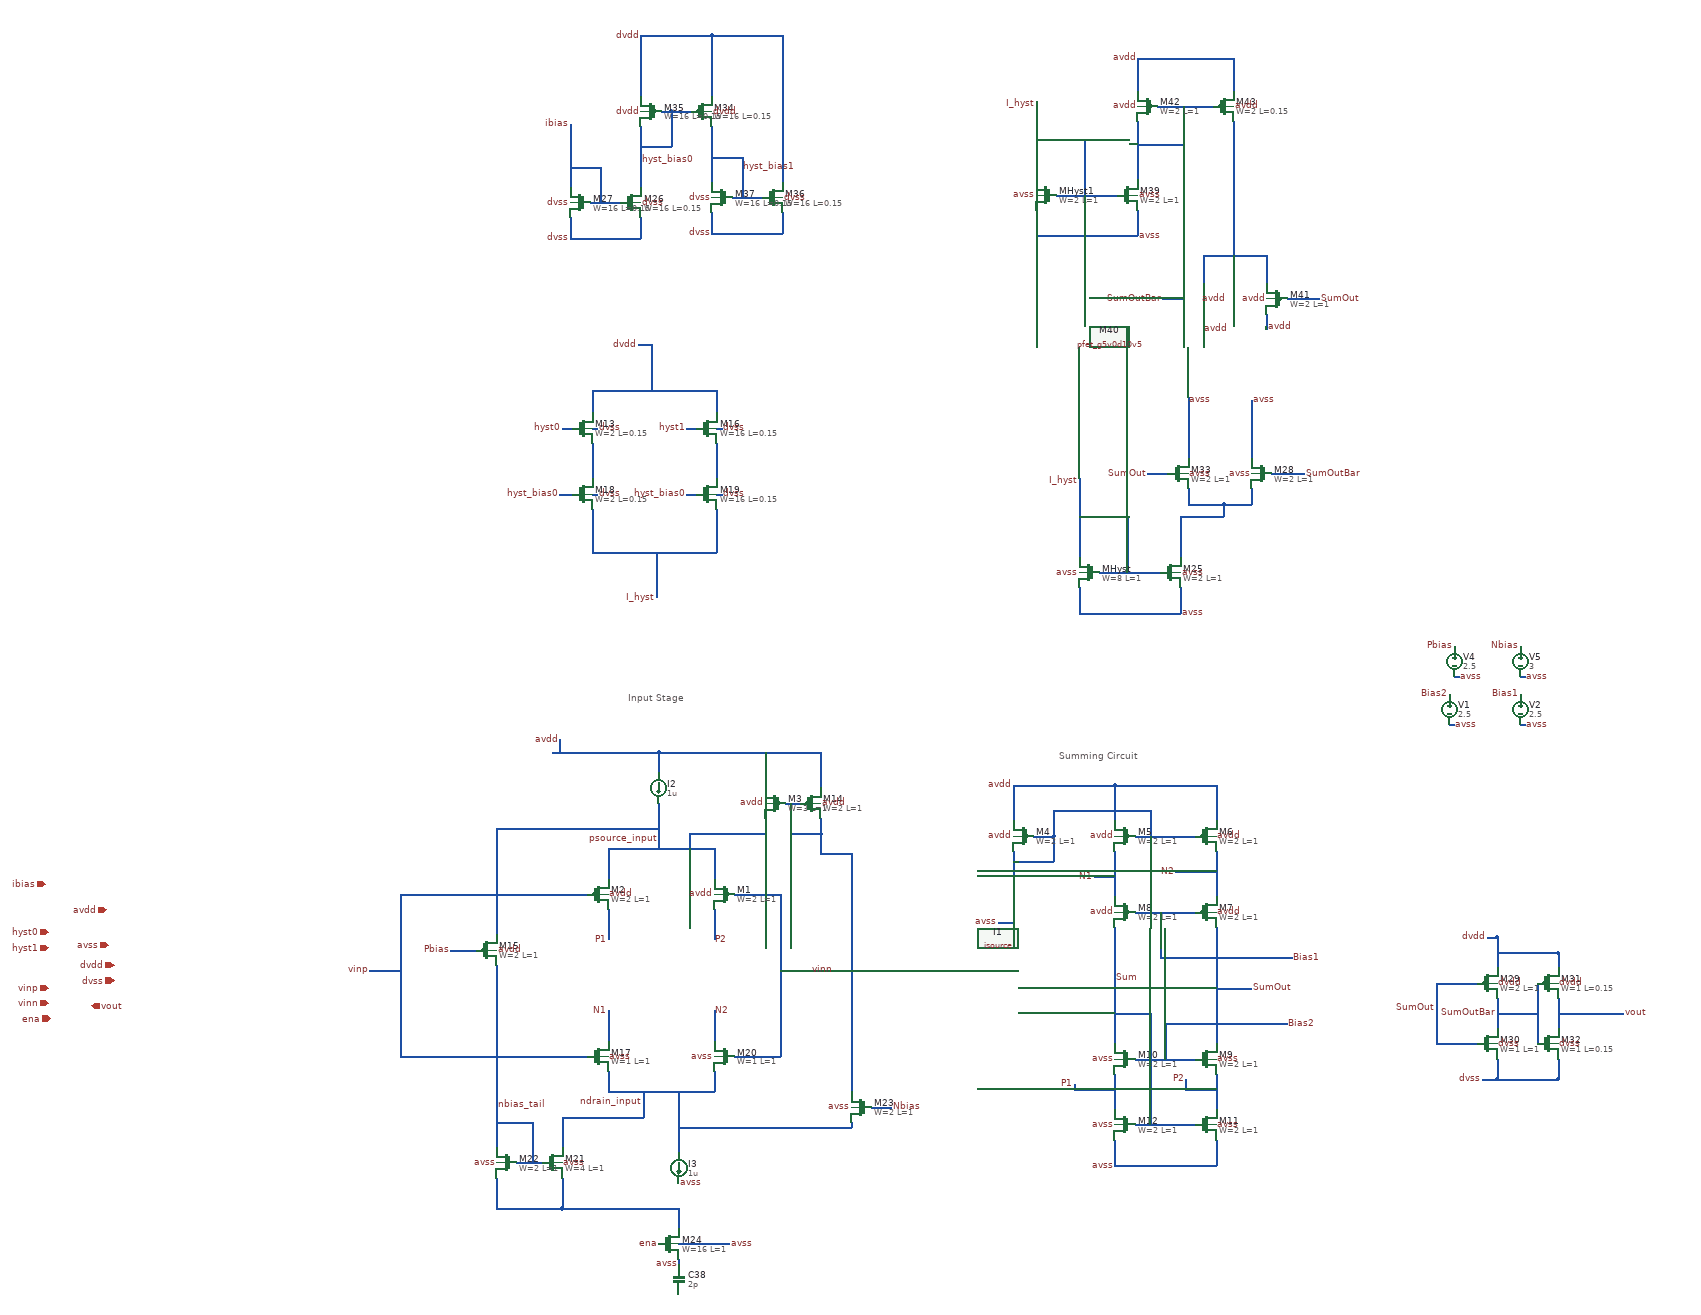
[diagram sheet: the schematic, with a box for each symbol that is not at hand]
v {xschem version=3.4.4 file_version=1.2
}
G {}
K {}
V {}
S {}
E {}
T {Summing Circuit} 2105 -1180 0 0 0.5 0.5 {}
T {Input Stage} 1255 -1295 0 0 0.5 0.5 {}
N 1185 -1815 1195 -1815 {
lab=dvss}
N 1310 -1500 1310 -1480 {
lab=I_hyst}
N 1430 -1815 1440 -1815 {
lab=dvss}
N 1370 -1815 1390 -1815 {
lab=hyst1}
N 1430 -1785 1430 -1715 {
lab=#net1}
N 1430 -1685 1440 -1685 {
lab=dvss}
N 1185 -1785 1185 -1715 {
lab=#net2}
N 1185 -1785 1185 -1715 {
lab=#net2}
N 1430 -1655 1430 -1625 {
lab=I_hyst}
N 1185 -1635 1185 -1570 {
lab=I_hyst}
N 1185 -1655 1185 -1635 {
lab=I_hyst}
N 1430 -1625 1430 -1570 {
lab=I_hyst}
N 1185 -1685 1195 -1685 {
lab=dvss}
N 1430 -1890 1430 -1845 {
lab=dvdd}
N 1185 -1890 1185 -1845 {
lab=dvdd}
N 1185 -1570 1430 -1570 {
lab=I_hyst}
N 1370 -1685 1390 -1685 {
lab=hyst_bias0}
N 1120 -1685 1145 -1685 {
lab=hyst_bias0}
N 1125 -1815 1145 -1815 {
lab=hyst0}
N 2970 -690 2970 -630 {
lab=SumOutBar}
N 3090 -660 3220 -660 {
lab=vout}
N 2970 -810 2970 -750 {
lab=dvdd}
N 2950 -810 2970 -810 {
lab=dvdd}
N 2970 -570 2970 -530 {
lab=dvss}
N 2940 -530 2970 -530 {
lab=dvss}
N 2885 -1325 2895 -1325 {
lab=avss}
N 3015 -1325 3025 -1325 {
lab=avss}
N 3090 -690 3090 -630 {
lab=vout}
N 3050 -720 3050 -600 {
lab=SumOutBar}
N 3090 -780 3090 -750 {
lab=dvdd}
N 2970 -780 3090 -780 {
lab=dvdd}
N 3090 -570 3090 -530 {
lab=dvss}
N 2970 -530 3090 -530 {
lab=dvss}
N 2970 -690 2970 -630 {
lab=SumOutBar}
N 2880 -720 2930 -720 {
lab=SumOut}
N 2880 -600 2930 -600 {
lab=SumOut}
N 3090 -660 3220 -660 {
lab=vout}
N 2970 -810 2970 -750 {
lab=dvdd}
N 2950 -810 2970 -810 {
lab=dvdd}
N 2970 -570 2970 -530 {
lab=dvss}
N 2940 -530 2970 -530 {
lab=dvss}
N 3090 -690 3090 -630 {
lab=vout}
N 3050 -720 3050 -600 {
lab=SumOutBar}
N 3090 -780 3090 -750 {
lab=dvdd}
N 2970 -780 3090 -780 {
lab=dvdd}
N 3090 -570 3090 -530 {
lab=dvss}
N 2970 -530 3090 -530 {
lab=dvss}
N 2970 -660 3050 -660 {
lab=SumOutBar}
N 2015 -980 2015 -930 {
lab=#net3}
N 2015 -960 2095 -960 {
lab=#net3}
N 2095 -1010 2095 -960 {
lab=#net3}
N 2055 -1010 2095 -1010 {
lab=#net3}
N 2015 -1110 2015 -1040 {
lab=avdd}
N 2015 -1110 2215 -1110 {
lab=avdd}
N 2215 -1110 2215 -1040 {
lab=avdd}
N 2215 -1110 2395 -1110 {
lab=avdd}
N 2415 -1110 2415 -1040 {
lab=avdd}
N 2395 -1110 2415 -1110 {
lab=avdd}
N 2255 -1010 2375 -1010 {
lab=#net3}
N 2285 -1060 2285 -1010 {
lab=#net3}
N 2095 -1060 2285 -1060 {
lab=#net3}
N 2095 -1060 2095 -1010 {
lab=#net3}
N 2215 -980 2215 -920 {
lab=N1}
N 2415 -980 2415 -890 {
lab=N2}
N 2335 -940 2415 -940 {
lab=N2}
N 2335 -860 2375 -860 {
lab=Bias1}
N 2255 -860 2335 -860 {
lab=Bias1}
N 2215 -920 2215 -890 {
lab=N1}
N 2415 -830 2415 -600 {
lab=SumOut}
N 2215 -830 2215 -600 {
lab=Sum}
N 2255 -570 2375 -570 {
lab=Bias2}
N 2415 -540 2415 -470 {
lab=P2}
N 2355 -510 2415 -510 {
lab=P2}
N 2355 -530 2355 -510 {
lab=P2}
N 2215 -540 2215 -470 {
lab=P1}
N 2255 -440 2375 -440 {
lab=Sum}
N 2215 -410 2215 -360 {
lab=avss}
N 2215 -360 2415 -360 {
lab=avss}
N 2415 -410 2415 -360 {
lab=avss}
N 2135 -510 2215 -510 {
lab=P1}
N 2135 -520 2135 -510 {
lab=P1}
N 2285 -660 2285 -440 {
lab=Sum}
N 2215 -660 2285 -660 {
lab=Sum}
N 2175 -930 2215 -930 {
lab=N1}
N 2305 -860 2305 -770 {
lab=Bias1}
N 2305 -770 2565 -770 {
lab=Bias1}
N 2315 -640 2315 -570 {
lab=Bias2}
N 2315 -640 2555 -640 {
lab=Bias2}
N 2015 -870 2015 -840 {
lab=avss}
N 1985 -840 2015 -840 {
lab=avss}
N 2415 -710 2485 -710 {
lab=SumOut}
N 1355 -205 1455 -205 {lab=avss}
N 1355 -175 1355 -145 {lab=avss}
N 1425 -985 1425 -925 {
lab=psource_input}
N 1215 -985 1425 -985 {
lab=psource_input}
N 1215 -985 1215 -925 {
lab=psource_input}
N 1315 -1015 1315 -985 {
lab=psource_input}
N 1265 -1175 1315 -1175 {
lab=avdd}
N 1565 -1075 1595 -1075 {
lab=#net4}
N 1315 -1175 1585 -1175 {
lab=avdd}
N 1635 -1175 1635 -1105 {
lab=avdd}
N 1525 -1175 1525 -1105 {
lab=avdd}
N 1575 -1075 1575 -1015 {
lab=#net4}
N 1575 -1015 1635 -1015 {
lab=#net4}
N 1635 -1045 1635 -1015 {
lab=#net4}
N 1525 -1045 1525 -1015 {
lab=psource_input}
N 1375 -1015 1475 -1015 {
lab=psource_input}
N 1375 -1015 1375 -985 {
lab=psource_input}
N 1425 -865 1425 -805 {
lab=P2}
N 1215 -865 1215 -805 {
lab=P1}
N 1105 -1025 1315 -1025 {
lab=psource_input}
N 995 -975 995 -925 {
lab=psource_input}
N 995 -1025 995 -975 {
lab=psource_input}
N 1045 -1025 1105 -1025 {
lab=psource_input}
N 905 -785 955 -785 {
lab=Pbias}
N 995 -925 995 -815 {
lab=psource_input}
N 805 -895 1175 -895 {
lab=vinp}
N 1425 -655 1425 -605 {
lab=N2}
N 1215 -665 1215 -605 {
lab=N1}
N 1425 -665 1425 -655 {
lab=N2}
N 1035 -365 1085 -365 {
lab=nbias_tail}
N 1215 -545 1215 -505 {
lab=ndrain_input}
N 1215 -505 1425 -505 {
lab=ndrain_input}
N 1425 -545 1425 -505 {
lab=ndrain_input}
N 1285 -505 1285 -455 {
lab=ndrain_input}
N 1125 -455 1285 -455 {
lab=ndrain_input}
N 1125 -455 1125 -395 {
lab=ndrain_input}
N 995 -1025 1045 -1025 {
lab=psource_input}
N 995 -755 995 -395 {
lab=nbias_tail}
N 805 -575 1175 -575 {
lab=vinp}
N 995 -335 995 -275 {
lab=#net5}
N 995 -275 1125 -275 {
lab=#net5}
N 1125 -335 1125 -275 {
lab=#net5}
N 1465 -575 1555 -575 {
lab=vinn}
N 1355 -505 1355 -385 {
lab=ndrain_input}
N 1475 -1015 1525 -1015 {
lab=psource_input}
N 1585 -1175 1635 -1175 {
lab=avdd}
N 1465 -895 1485 -895 {
lab=vinn}
N 1485 -895 1505 -895 {
lab=vinn}
N 1555 -895 1555 -575 {
lab=vinn}
N 1505 -895 1555 -895 {
lab=vinn}
N 1555 -745 1585 -745 {
lab=vinn}
N 1585 -745 1615 -745 {
lab=vinn}
N 1065 -445 1065 -365 {
lab=nbias_tail}
N 995 -445 1065 -445 {
lab=nbias_tail}
N 1355 -435 1635 -435 {
lab=ndrain_input}
N 1635 -435 1695 -435 {
lab=ndrain_input}
N 1695 -445 1695 -435 {
lab=ndrain_input}
N 1695 -975 1695 -505 {
lab=#net4}
N 1635 -975 1695 -975 {
lab=#net4}
N 1635 -1015 1635 -975 {
lab=#net4}
N 1735 -475 1775 -475 {
lab=Nbias}
N 1105 -1175 1265 -1175 {
lab=avdd}
N 1120 -1200 1120 -1175 {
lab=avdd}
N 1315 -1025 1315 -1015 {
lab=psource_input}
N 1125 -275 1195 -275 {
lab=#net5}
N 805 -895 805 -575 {
lab=vinp}
N 745 -745 775 -745 {
lab=vinp}
N 775 -745 805 -745 {
lab=vinp}
N 1315 -1075 1315 -1020 {
lab=psource_input}
N 1315 -1175 1315 -1135 {
lab=avdd}
N 2185 -1530 2305 -1530 {
lab=I_hyst}
N 2145 -1500 2145 -1450 {
lab=avss}
N 2145 -1450 2345 -1450 {
lab=avss}
N 2345 -1500 2345 -1450 {
lab=avss}
N 2145 -1715 2145 -1560 {
lab=I_hyst}
N 2240 -1640 2240 -1530 {
lab=I_hyst}
N 2145 -1640 2240 -1640 {
lab=I_hyst}
N 2280 -1725 2320 -1725 {
lab=SumOut}
N 2345 -1640 2360 -1640 {
lab=#net6}
N 2345 -1640 2345 -1560 {
lab=#net6}
N 2360 -1640 2430 -1640 {
lab=#net6}
N 2430 -1665 2430 -1640 {
lab=#net6}
N 2360 -1665 2430 -1665 {
lab=#net6}
N 2360 -1695 2360 -1665 {
lab=#net6}
N 2430 -1665 2485 -1665 {
lab=#net6}
N 2485 -1695 2485 -1665 {
lab=#net6}
N 2485 -1870 2485 -1755 {
lab=avss}
N 2360 -1805 2360 -1755 {
lab=avss}
N 2525 -1725 2590 -1725 {
lab=SumOutBar}
N 1140 -2230 1140 -2190 {
lab=dvss}
N 1140 -2190 1280 -2190 {
lab=dvss}
N 1280 -2230 1280 -2190 {
lab=dvss}
N 1180 -2260 1240 -2260 {
lab=ibias}
N 1140 -2415 1140 -2290 {
lab=ibias}
N 1200 -2330 1200 -2260 {
lab=ibias}
N 1140 -2330 1200 -2330 {
lab=ibias}
N 1280 -2410 1280 -2290 {
lab=hyst_bias0}
N 1280 -2370 1340 -2370 {
lab=hyst_bias0}
N 1340 -2440 1340 -2370 {
lab=hyst_bias0}
N 1320 -2440 1340 -2440 {
lab=hyst_bias0}
N 1340 -2440 1380 -2440 {
lab=hyst_bias0}
N 1280 -2590 1280 -2470 {
lab=dvdd}
N 1280 -2590 1420 -2590 {
lab=dvdd}
N 1420 -2590 1420 -2470 {
lab=dvdd}
N 1185 -1890 1430 -1890 {
lab=dvdd}
N 1300 -1980 1300 -1890 {
lab=dvdd}
N 1275 -1980 1300 -1980 {
lab=dvdd}
N 1420 -2240 1420 -2200 {
lab=dvss}
N 1420 -2200 1560 -2200 {
lab=dvss}
N 1560 -2240 1560 -2200 {
lab=dvss}
N 1460 -2270 1520 -2270 {
lab=hyst_bias1}
N 1420 -2410 1420 -2300 {
lab=hyst_bias1}
N 1480 -2350 1480 -2270 {
lab=hyst_bias1}
N 1420 -2350 1480 -2350 {
lab=hyst_bias1}
N 1560 -2590 1560 -2300 {
lab=dvdd}
N 1420 -2590 1560 -2590 {
lab=dvdd}
N 3015 -1230 3025 -1230 {
lab=avss}
N 2850 -720 2850 -600 {
lab=SumOut}
N 2850 -600 2880 -600 {
lab=SumOut}
N 2850 -720 2880 -720 {
lab=SumOut}
N 1195 -275 1355 -275 {
lab=#net5}
N 1355 -275 1355 -240 {
lab=#net5}
N 1355 -240 1355 -235 {
lab=#net5}
N 1310 -1570 1310 -1560 {
lab=I_hyst}
N 1310 -1560 1310 -1500 {
lab=I_hyst}
N 2360 -1875 2360 -1805 {
lab=avss}
N 2875 -1230 2885 -1230 {
lab=avss}
N 2100 -2275 2220 -2275 {
lab=I_hyst}
N 2060 -2245 2060 -2195 {
lab=avss}
N 2060 -2195 2260 -2195 {
lab=avss}
N 2260 -2245 2260 -2195 {
lab=avss}
N 2060 -2460 2060 -2305 {
lab=I_hyst}
N 2155 -2385 2155 -2275 {
lab=I_hyst}
N 2060 -2385 2155 -2385 {
lab=I_hyst}
N 2310 -2070 2350 -2070 {
lab=SumOutBar}
N 2260 -2385 2260 -2305 {
lab=#net7}
N 2390 -2040 2390 -2010 {
lab=avdd}
N 2515 -2040 2515 -2010 {
lab=avdd}
N 2390 -2150 2390 -2100 {
lab=#net8}
N 2555 -2070 2620 -2070 {
lab=SumOut}
N 2515 -2155 2515 -2100 {
lab=#net8}
N 2390 -2155 2515 -2155 {
lab=#net8}
N 2390 -2155 2390 -2150 {
lab=#net8}
N 2260 -2420 2260 -2385 {
lab=#net7}
N 2300 -2450 2410 -2450 {
lab=#net7}
N 2450 -2420 2450 -2155 {
lab=#net8}
N 2260 -2545 2260 -2480 {
lab=avdd}
N 2260 -2545 2450 -2545 {
lab=avdd}
N 2450 -2545 2450 -2480 {
lab=avdd}
N 2260 -2375 2350 -2375 {
lab=#net7}
N 2350 -2450 2350 -2375 {
lab=#net7}
C {devices/ipin.sym} 110 -710 0 0 {name=p48 lab=vinp
}
C {devices/ipin.sym} 110 -680 0 0 {name=p4 lab=vinn
}
C {devices/ipin.sym} 110 -820 0 0 {name=p19 lab=hyst0
}
C {devices/ipin.sym} 110 -790 0 0 {name=p20 lab=hyst1
}
C {devices/lab_pin.sym} 1310 -1480 0 0 {name=p31 sig_type=std_logic lab=I_hyst

}
C {devices/ipin.sym} 225 -865 0 0 {name=p37 lab=avdd
}
C {devices/ipin.sym} 230 -795 0 0 {name=p38 lab=avss
}
C {devices/ipin.sym} 240 -755 0 0 {name=p39 lab=dvdd
}
C {devices/ipin.sym} 240 -725 0 0 {name=p40 lab=dvss
}
C {devices/opin.sym} 195 -675 0 0 { name=p116 lab=vout}
C {devices/ipin.sym} 115 -650 0 0 {name=p42 lab=ena
}
C {devices/lab_pin.sym} 1370 -1815 0 0 {name=p18 sig_type=std_logic lab=hyst1

}
C {sky130_fd_pr/nfet_01v8.sym} 1410 -1815 0 0 {name=M16
L=0.15
W=16
mult=8 nf=1
model=nfet_01v8
spiceprefix=X}
C {sky130_fd_pr/nfet_01v8.sym} 1410 -1685 0 0 {name=M19
L=0.15
W=16
mult=8 nf=1
model=nfet_01v8
spiceprefix=X}
C {devices/ipin.sym} 105 -915 0 0 {name=p27 lab=ibias
}
C {devices/lab_pin.sym} 1195 -1685 0 1 {name=p33 sig_type=std_logic lab=dvss

}
C {devices/lab_pin.sym} 1125 -1815 0 0 {name=p25 sig_type=std_logic lab=hyst0

}
C {devices/lab_pin.sym} 1120 -1685 0 0 {name=p26 sig_type=std_logic lab=hyst_bias0


}
C {devices/lab_pin.sym} 1195 -1815 0 1 {name=p23 sig_type=std_logic lab=dvss

}
C {devices/lab_pin.sym} 1440 -1685 0 1 {name=p30 sig_type=std_logic lab=dvss

}
C {devices/vsource.sym} 2885 -1355 0 0 {name=V4 value=2.5 savecurrent=false}
C {devices/vsource.sym} 3015 -1355 0 0 {name=V5 value=3 savecurrent=false}
C {devices/lab_pin.sym} 3015 -1385 0 0 {name=p36 sig_type=std_logic lab=Nbias


}
C {devices/lab_pin.sym} 2895 -1325 0 1 {name=p32 lab=avss
}
C {devices/lab_pin.sym} 3025 -1325 0 1 {name=p35 lab=avss
}
C {sky130_fd_pr/pfet_01v8.sym} 2950 -720 0 0 {name=M29
L=1
W=2
nf=1
mult=2
ad="'int((nf+1)/2) * W/nf * 0.29'" 
pd="'2*int((nf+1)/2) * (W/nf + 0.29)'"
as="'int((nf+2)/2) * W/nf * 0.29'" 
ps="'2*int((nf+2)/2) * (W/nf + 0.29)'"
nrd="'0.29 / W'" nrs="'0.29 / W'"
sa=0 sb=0 sd=0
model=pfet_01v8
spiceprefix=X
}
C {devices/lab_pin.sym} 3220 -660 0 1 {name=l39 lab=vout
}
C {devices/lab_pin.sym} 2950 -810 0 0 {name=l40 lab=dvdd
}
C {devices/lab_pin.sym} 2940 -530 0 0 {name=l41 lab=dvss
}
C {sky130_fd_pr/nfet_01v8.sym} 2950 -600 0 0 {name=M30
L=1
W=1
nf=1 
mult=2
ad="'int((nf+1)/2) * W/nf * 0.29'" 
pd="'2*int((nf+1)/2) * (W/nf + 0.29)'"
as="'int((nf+2)/2) * W/nf * 0.29'" 
ps="'2*int((nf+2)/2) * (W/nf + 0.29)'"
nrd="'0.29 / W'" nrs="'0.29 / W'"
sa=0 sb=0 sd=0
model=nfet_01v8
spiceprefix=X
}
C {sky130_fd_pr/pfet_01v8.sym} 3070 -720 0 0 {name=M31
L=0.15
W=1
nf=1
mult=1
ad="'int((nf+1)/2) * W/nf * 0.29'" 
pd="'2*int((nf+1)/2) * (W/nf + 0.29)'"
as="'int((nf+2)/2) * W/nf * 0.29'" 
ps="'2*int((nf+2)/2) * (W/nf + 0.29)'"
nrd="'0.29 / W'" nrs="'0.29 / W'"
sa=0 sb=0 sd=0
model=pfet_01v8
spiceprefix=X
}
C {sky130_fd_pr/nfet_01v8.sym} 3070 -600 0 0 {name=M32
L=0.15
W=1
nf=1 
mult=1
ad="'int((nf+1)/2) * W/nf * 0.29'" 
pd="'2*int((nf+1)/2) * (W/nf + 0.29)'"
as="'int((nf+2)/2) * W/nf * 0.29'" 
ps="'2*int((nf+2)/2) * (W/nf + 0.29)'"
nrd="'0.29 / W'" nrs="'0.29 / W'"
sa=0 sb=0 sd=0
model=nfet_01v8
spiceprefix=X
}
C {devices/lab_pin.sym} 3090 -600 0 1 {name=l42 lab=dvss
}
C {devices/lab_pin.sym} 2970 -600 0 1 {name=l43 lab=dvss
}
C {devices/lab_pin.sym} 2970 -720 0 1 {name=l44 lab=dvdd
}
C {devices/lab_pin.sym} 3090 -720 0 1 {name=l45 lab=dvdd
}
C {sky130_fd_pr/pfet_g5v0d10v5.sym} 2035 -1010 0 1 {name=M4
L=1
W=2
nf=1
mult=2
ad="'int((nf+1)/2) * W/nf * 0.29'" 
pd="'2*int((nf+1)/2) * (W/nf + 0.29)'"
as="'int((nf+2)/2) * W/nf * 0.29'" 
ps="'2*int((nf+2)/2) * (W/nf + 0.29)'"
nrd="'0.29 / W'" nrs="'0.29 / W'"
sa=0 sb=0 sd=0
model=pfet_g5v0d10v5
spiceprefix=X
}
C {sky130_fd_pr/pfet_g5v0d10v5.sym} 2235 -1010 0 1 {name=M5
L=1
W=2
nf=1
mult=2
ad="'int((nf+1)/2) * W/nf * 0.29'" 
pd="'2*int((nf+1)/2) * (W/nf + 0.29)'"
as="'int((nf+2)/2) * W/nf * 0.29'" 
ps="'2*int((nf+2)/2) * (W/nf + 0.29)'"
nrd="'0.29 / W'" nrs="'0.29 / W'"
sa=0 sb=0 sd=0
model=pfet_g5v0d10v5
spiceprefix=X
}
C {sky130_fd_pr/pfet_g5v0d10v5.sym} 2395 -1010 0 0 {name=M6
L=1
W=2
nf=1
mult=2
ad="'int((nf+1)/2) * W/nf * 0.29'" 
pd="'2*int((nf+1)/2) * (W/nf + 0.29)'"
as="'int((nf+2)/2) * W/nf * 0.29'" 
ps="'2*int((nf+2)/2) * (W/nf + 0.29)'"
nrd="'0.29 / W'" nrs="'0.29 / W'"
sa=0 sb=0 sd=0
model=pfet_g5v0d10v5
spiceprefix=X
}
C {sky130_fd_pr/pfet_g5v0d10v5.sym} 2395 -860 0 0 {name=M7
L=1
W=2
nf=1
mult=2
ad="'int((nf+1)/2) * W/nf * 0.29'" 
pd="'2*int((nf+1)/2) * (W/nf + 0.29)'"
as="'int((nf+2)/2) * W/nf * 0.29'" 
ps="'2*int((nf+2)/2) * (W/nf + 0.29)'"
nrd="'0.29 / W'" nrs="'0.29 / W'"
sa=0 sb=0 sd=0
model=pfet_g5v0d10v5
spiceprefix=X
}
C {sky130_fd_pr/pfet_g5v0d10v5.sym} 2235 -860 0 1 {name=M8
L=1
W=2
nf=1
mult=2
ad="'int((nf+1)/2) * W/nf * 0.29'" 
pd="'2*int((nf+1)/2) * (W/nf + 0.29)'"
as="'int((nf+2)/2) * W/nf * 0.29'" 
ps="'2*int((nf+2)/2) * (W/nf + 0.29)'"
nrd="'0.29 / W'" nrs="'0.29 / W'"
sa=0 sb=0 sd=0
model=pfet_g5v0d10v5
spiceprefix=X
}
C {sky130_fd_pr/nfet_g5v0d10v5.sym} 2395 -570 0 0 {name=M9
L=1
W=2
nf=1
mult=2
ad="'int((nf+1)/2) * W/nf * 0.29'" 
pd="'2*int((nf+1)/2) * (W/nf + 0.29)'"
as="'int((nf+2)/2) * W/nf * 0.29'" 
ps="'2*int((nf+2)/2) * (W/nf + 0.29)'"
nrd="'0.29 / W'" nrs="'0.29 / W'"
sa=0 sb=0 sd=0
model=nfet_g5v0d10v5
spiceprefix=X
}
C {devices/lab_pin.sym} 2335 -940 0 0 {name=l1 lab=N2}
C {sky130_fd_pr/nfet_g5v0d10v5.sym} 2235 -570 0 1 {name=M10
L=1
W=2
nf=1
mult=2
ad="'int((nf+1)/2) * W/nf * 0.29'" 
pd="'2*int((nf+1)/2) * (W/nf + 0.29)'"
as="'int((nf+2)/2) * W/nf * 0.29'" 
ps="'2*int((nf+2)/2) * (W/nf + 0.29)'"
nrd="'0.29 / W'" nrs="'0.29 / W'"
sa=0 sb=0 sd=0
model=nfet_g5v0d10v5
spiceprefix=X
}
C {sky130_fd_pr/nfet_g5v0d10v5.sym} 2395 -440 0 0 {name=M11
L=1
W=2
nf=1
mult=2
ad="'int((nf+1)/2) * W/nf * 0.29'" 
pd="'2*int((nf+1)/2) * (W/nf + 0.29)'"
as="'int((nf+2)/2) * W/nf * 0.29'" 
ps="'2*int((nf+2)/2) * (W/nf + 0.29)'"
nrd="'0.29 / W'" nrs="'0.29 / W'"
sa=0 sb=0 sd=0
model=nfet_g5v0d10v5
spiceprefix=X
}
C {devices/lab_pin.sym} 2355 -530 0 0 {name=l2 lab=P2
}
C {sky130_fd_pr/nfet_g5v0d10v5.sym} 2235 -440 0 1 {name=M12
L=1
W=2
nf=1
mult=2
ad="'int((nf+1)/2) * W/nf * 0.29'" 
pd="'2*int((nf+1)/2) * (W/nf + 0.29)'"
as="'int((nf+2)/2) * W/nf * 0.29'" 
ps="'2*int((nf+2)/2) * (W/nf + 0.29)'"
nrd="'0.29 / W'" nrs="'0.29 / W'"
sa=0 sb=0 sd=0
model=nfet_g5v0d10v5
spiceprefix=X
}
C {devices/lab_pin.sym} 2135 -520 0 0 {name=l3 lab=P1
}
C {devices/lab_pin.sym} 2175 -930 0 0 {name=l4 lab=N1}
C {devices/lab_pin.sym} 2565 -770 0 1 {name=l5 lab=Bias1
}
C {devices/isource.sym} 2015 -905 0 0 {name=I1 value=1u}
C {devices/lab_pin.sym} 1985 -840 0 0 {name=p1 lab=avss
}
C {devices/lab_pin.sym} 2015 -1010 0 0 {name=l24 lab=avdd
}
C {devices/lab_pin.sym} 2215 -1010 0 0 {name=l25 lab=avdd
}
C {devices/lab_pin.sym} 2415 -1010 0 1 {name=l26 lab=avdd
}
C {devices/lab_pin.sym} 2415 -860 0 1 {name=l27 lab=avdd
}
C {devices/lab_pin.sym} 2215 -860 0 0 {name=l28 lab=avdd
}
C {devices/lab_pin.sym} 2015 -1110 0 0 {name=l29 lab=avdd
}
C {devices/lab_pin.sym} 2215 -570 0 0 {name=p8 lab=avss
}
C {devices/lab_pin.sym} 2415 -570 0 1 {name=p9 lab=avss
}
C {devices/lab_pin.sym} 2415 -440 0 1 {name=p10 lab=avss
}
C {devices/lab_pin.sym} 2215 -440 0 0 {name=p11 lab=avss
}
C {devices/lab_pin.sym} 2215 -360 0 0 {name=p12 lab=avss
}
C {devices/lab_pin.sym} 1315 -205 0 0 {name=l56 lab=ena}
C {devices/lab_pin.sym} 1355 -165 0 0 {name=p284 lab=avss
}
C {devices/parax_cap.sym} 1355 -135 0 0 {name=C38  value=2p}
C {devices/lab_pin.sym} 1455 -205 0 1 {name=p43 sig_type=std_logic lab=avss


}
C {sky130_fd_pr/nfet_g5v0d10v5.sym} 1335 -205 0 0 {name=M24
L=1
W=16
nf=1
mult=2
ad="'int((nf+1)/2) * W/nf * 0.29'" 
pd="'2*int((nf+1)/2) * (W/nf + 0.29)'"
as="'int((nf+2)/2) * W/nf * 0.29'" 
ps="'2*int((nf+2)/2) * (W/nf + 0.29)'"
nrd="'0.29 / W'" nrs="'0.29 / W'"
sa=0 sb=0 sd=0
model=nfet_g5v0d10v5
spiceprefix=X
}
C {sky130_fd_pr/pfet_g5v0d10v5.sym} 1445 -895 0 1 {name=M1
L=1
W=2
nf=1
mult=2
ad="'int((nf+1)/2) * W/nf * 0.29'" 
pd="'2*int((nf+1)/2) * (W/nf + 0.29)'"
as="'int((nf+2)/2) * W/nf * 0.29'" 
ps="'2*int((nf+2)/2) * (W/nf + 0.29)'"
nrd="'0.29 / W'" nrs="'0.29 / W'"
sa=0 sb=0 sd=0
model=pfet_g5v0d10v5
spiceprefix=X
}
C {sky130_fd_pr/pfet_g5v0d10v5.sym} 1195 -895 0 0 {name=M2
L=1
W=2
nf=1
mult=2
ad="'int((nf+1)/2) * W/nf * 0.29'" 
pd="'2*int((nf+1)/2) * (W/nf + 0.29)'"
as="'int((nf+2)/2) * W/nf * 0.29'" 
ps="'2*int((nf+2)/2) * (W/nf + 0.29)'"
nrd="'0.29 / W'" nrs="'0.29 / W'"
sa=0 sb=0 sd=0
model=pfet_g5v0d10v5
spiceprefix=X
}
C {sky130_fd_pr/pfet_g5v0d10v5.sym} 1545 -1075 0 1 {name=M3
L=1
W=3
nf=1
mult=4
ad="'int((nf+1)/2) * W/nf * 0.29'" 
pd="'2*int((nf+1)/2) * (W/nf + 0.29)'"
as="'int((nf+2)/2) * W/nf * 0.29'" 
ps="'2*int((nf+2)/2) * (W/nf + 0.29)'"
nrd="'0.29 / W'" nrs="'0.29 / W'"
sa=0 sb=0 sd=0
model=pfet_g5v0d10v5
spiceprefix=X
}
C {sky130_fd_pr/pfet_g5v0d10v5.sym} 1615 -1075 0 0 {name=M14
L=1
W=2
nf=1
mult=2
ad="'int((nf+1)/2) * W/nf * 0.29'" 
pd="'2*int((nf+1)/2) * (W/nf + 0.29)'"
as="'int((nf+2)/2) * W/nf * 0.29'" 
ps="'2*int((nf+2)/2) * (W/nf + 0.29)'"
nrd="'0.29 / W'" nrs="'0.29 / W'"
sa=0 sb=0 sd=0
model=pfet_g5v0d10v5
spiceprefix=X
}
C {devices/lab_pin.sym} 1425 -805 0 1 {name=l7 lab=P2}
C {devices/lab_pin.sym} 1215 -805 0 0 {name=l8 lab=P1}
C {sky130_fd_pr/pfet_g5v0d10v5.sym} 975 -785 0 0 {name=M15
L=1
W=2
nf=1
mult=2
ad="'int((nf+1)/2) * W/nf * 0.29'" 
pd="'2*int((nf+1)/2) * (W/nf + 0.29)'"
as="'int((nf+2)/2) * W/nf * 0.29'" 
ps="'2*int((nf+2)/2) * (W/nf + 0.29)'"
nrd="'0.29 / W'" nrs="'0.29 / W'"
sa=0 sb=0 sd=0
model=pfet_g5v0d10v5
spiceprefix=X
}
C {sky130_fd_pr/nfet_g5v0d10v5.sym} 1195 -575 0 0 {name=M17
L=1
W=1
nf=1
mult=2
ad="'int((nf+1)/2) * W/nf * 0.29'" 
pd="'2*int((nf+1)/2) * (W/nf + 0.29)'"
as="'int((nf+2)/2) * W/nf * 0.29'" 
ps="'2*int((nf+2)/2) * (W/nf + 0.29)'"
nrd="'0.29 / W'" nrs="'0.29 / W'"
sa=0 sb=0 sd=0
model=nfet_g5v0d10v5
spiceprefix=X
}
C {sky130_fd_pr/nfet_g5v0d10v5.sym} 1445 -575 0 1 {name=M20
L=1
W=1
nf=1
mult=2
ad="'int((nf+1)/2) * W/nf * 0.29'" 
pd="'2*int((nf+1)/2) * (W/nf + 0.29)'"
as="'int((nf+2)/2) * W/nf * 0.29'" 
ps="'2*int((nf+2)/2) * (W/nf + 0.29)'"
nrd="'0.29 / W'" nrs="'0.29 / W'"
sa=0 sb=0 sd=0
model=nfet_g5v0d10v5
spiceprefix=X
}
C {devices/lab_pin.sym} 1425 -665 0 1 {name=l10 lab=N2}
C {devices/lab_pin.sym} 1215 -665 0 0 {name=l11 lab=N1}
C {sky130_fd_pr/nfet_g5v0d10v5.sym} 1105 -365 0 0 {name=M21
L=1
W=4
nf=1
mult=2
ad="'int((nf+1)/2) * W/nf * 0.29'" 
pd="'2*int((nf+1)/2) * (W/nf + 0.29)'"
as="'int((nf+2)/2) * W/nf * 0.29'" 
ps="'2*int((nf+2)/2) * (W/nf + 0.29)'"
nrd="'0.29 / W'" nrs="'0.29 / W'"
sa=0 sb=0 sd=0
model=nfet_g5v0d10v5
spiceprefix=X
}
C {sky130_fd_pr/nfet_g5v0d10v5.sym} 1015 -365 0 1 {name=M22
L=1
W=2
nf=1
mult=2
ad="'int((nf+1)/2) * W/nf * 0.29'" 
pd="'2*int((nf+1)/2) * (W/nf + 0.29)'"
as="'int((nf+2)/2) * W/nf * 0.29'" 
ps="'2*int((nf+2)/2) * (W/nf + 0.29)'"
nrd="'0.29 / W'" nrs="'0.29 / W'"
sa=0 sb=0 sd=0
model=nfet_g5v0d10v5
spiceprefix=X
}
C {devices/lab_pin.sym} 1615 -745 0 1 {name=l13 lab=vinn
}
C {devices/lab_pin.sym} 1120 -1200 0 0 {name=l14 lab=avdd
}
C {sky130_fd_pr/nfet_g5v0d10v5.sym} 1715 -475 0 1 {name=M23
L=1
W=2
nf=1
mult=2
ad="'int((nf+1)/2) * W/nf * 0.29'" 
pd="'2*int((nf+1)/2) * (W/nf + 0.29)'"
as="'int((nf+2)/2) * W/nf * 0.29'" 
ps="'2*int((nf+2)/2) * (W/nf + 0.29)'"
nrd="'0.29 / W'" nrs="'0.29 / W'"
sa=0 sb=0 sd=0
model=nfet_g5v0d10v5
spiceprefix=X
}
C {devices/lab_pin.sym} 1775 -475 0 1 {name=l16 lab=Nbias
}
C {devices/lab_pin.sym} 1425 -895 0 0 {name=l18 lab=avdd
}
C {devices/lab_pin.sym} 1215 -895 0 1 {name=l19 lab=avdd
}
C {devices/lab_pin.sym} 995 -785 0 1 {name=l21 lab=avdd
}
C {devices/lab_pin.sym} 1125 -365 0 1 {name=p2 sig_type=std_logic lab=avss


}
C {devices/lab_pin.sym} 995 -365 0 0 {name=p3 sig_type=std_logic lab=avss


}
C {devices/lab_pin.sym} 1425 -575 0 0 {name=p5 sig_type=std_logic lab=avss


}
C {devices/lab_pin.sym} 1215 -575 0 1 {name=p6 sig_type=std_logic lab=avss


}
C {devices/lab_pin.sym} 1695 -475 0 0 {name=p7 sig_type=std_logic lab=avss


}
C {devices/lab_pin.sym} 1525 -1075 0 0 {name=l22 lab=avdd
}
C {devices/lab_pin.sym} 1635 -1075 0 1 {name=l23 lab=avdd
}
C {devices/lab_pin.sym} 1315 -1005 0 0 {name=l34 lab=psource_input
}
C {devices/lab_pin.sym} 1285 -485 0 0 {name=l35 lab=ndrain_input
}
C {devices/lab_pin.sym} 745 -745 0 0 {name=l12 lab=vinp
}
C {devices/lab_pin.sym} 905 -785 0 0 {name=l17 lab=Pbias
}
C {sky130_fd_pr/nfet_g5v0d10v5.sym} 2325 -1530 0 0 {name=M25
L=1
W=2
nf=1
mult=2
ad="'int((nf+1)/2) * W/nf * 0.29'" 
pd="'2*int((nf+1)/2) * (W/nf + 0.29)'"
as="'int((nf+2)/2) * W/nf * 0.29'" 
ps="'2*int((nf+2)/2) * (W/nf + 0.29)'"
nrd="'0.29 / W'" nrs="'0.29 / W'"
sa=0 sb=0 sd=0
model=nfet_g5v0d10v5
spiceprefix=X
}
C {sky130_fd_pr/nfet_g5v0d10v5.sym} 2165 -1530 0 1 {name=MHyst
L=1
W=8
nf=1
mult=2
ad="'int((nf+1)/2) * W/nf * 0.29'" 
pd="'2*int((nf+1)/2) * (W/nf + 0.29)'"
as="'int((nf+2)/2) * W/nf * 0.29'" 
ps="'2*int((nf+2)/2) * (W/nf + 0.29)'"
nrd="'0.29 / W'" nrs="'0.29 / W'"
sa=0 sb=0 sd=0
model=nfet_g5v0d10v5
spiceprefix=X
}
C {devices/lab_pin.sym} 2345 -1530 0 1 {name=p41 lab=avss
}
C {devices/lab_pin.sym} 2145 -1530 0 0 {name=p44 lab=avss
}
C {sky130_fd_pr/nfet_g5v0d10v5.sym} 2505 -1725 0 1 {name=M28
L=1
W=2
nf=1
mult=2
ad="'int((nf+1)/2) * W/nf * 0.29'" 
pd="'2*int((nf+1)/2) * (W/nf + 0.29)'"
as="'int((nf+2)/2) * W/nf * 0.29'" 
ps="'2*int((nf+2)/2) * (W/nf + 0.29)'"
nrd="'0.29 / W'" nrs="'0.29 / W'"
sa=0 sb=0 sd=0
model=nfet_g5v0d10v5
spiceprefix=X
}
C {sky130_fd_pr/nfet_g5v0d10v5.sym} 2340 -1725 0 0 {name=M33
L=1
W=2
nf=1
mult=2
ad="'int((nf+1)/2) * W/nf * 0.29'" 
pd="'2*int((nf+1)/2) * (W/nf + 0.29)'"
as="'int((nf+2)/2) * W/nf * 0.29'" 
ps="'2*int((nf+2)/2) * (W/nf + 0.29)'"
nrd="'0.29 / W'" nrs="'0.29 / W'"
sa=0 sb=0 sd=0
model=nfet_g5v0d10v5
spiceprefix=X
}
C {devices/lab_pin.sym} 2360 -1725 0 1 {name=p47 lab=avss
}
C {devices/lab_pin.sym} 2485 -1725 0 0 {name=p49 lab=avss
}
C {devices/lab_pin.sym} 2885 -1385 0 0 {name=p50 sig_type=std_logic lab=Pbias


}
C {sky130_fd_pr/nfet_01v8.sym} 1260 -2260 0 0 {name=M26
L=0.15
W=16
mult=8 nf=1
model=nfet_01v8
spiceprefix=X}
C {sky130_fd_pr/nfet_01v8.sym} 1160 -2260 0 1 {name=M27
L=0.15
W=16
mult=8 nf=1
model=nfet_01v8
spiceprefix=X}
C {devices/lab_pin.sym} 1140 -2190 0 0 {name=p34 sig_type=std_logic lab=dvss

}
C {devices/lab_pin.sym} 1140 -2415 0 0 {name=p53 sig_type=std_logic lab=ibias


}
C {sky130_fd_pr/pfet_01v8.sym} 1400 -2440 0 0 {name=M34
L=0.15
W=16
nf=1
mult=8
ad="'int((nf+1)/2) * W/nf * 0.29'" 
pd="'2*int((nf+1)/2) * (W/nf + 0.29)'"
as="'int((nf+2)/2) * W/nf * 0.29'" 
ps="'2*int((nf+2)/2) * (W/nf + 0.29)'"
nrd="'0.29 / W'" nrs="'0.29 / W'"
sa=0 sb=0 sd=0
model=pfet_01v8
spiceprefix=X
}
C {sky130_fd_pr/pfet_01v8.sym} 1300 -2440 0 1 {name=M35
L=0.15
W=16
nf=1
mult=8
ad="'int((nf+1)/2) * W/nf * 0.29'" 
pd="'2*int((nf+1)/2) * (W/nf + 0.29)'"
as="'int((nf+2)/2) * W/nf * 0.29'" 
ps="'2*int((nf+2)/2) * (W/nf + 0.29)'"
nrd="'0.29 / W'" nrs="'0.29 / W'"
sa=0 sb=0 sd=0
model=pfet_01v8
spiceprefix=X
}
C {devices/lab_pin.sym} 1440 -1815 0 1 {name=p54 sig_type=std_logic lab=dvss

}
C {devices/lab_pin.sym} 1280 -2260 0 1 {name=p55 sig_type=std_logic lab=dvss

}
C {devices/lab_pin.sym} 1140 -2260 0 0 {name=p56 sig_type=std_logic lab=dvss

}
C {devices/lab_pin.sym} 1280 -2590 0 0 {name=p57 sig_type=std_logic lab=dvdd

}
C {devices/lab_pin.sym} 1280 -2345 0 1 {name=p59 sig_type=std_logic lab=hyst_bias0


}
C {devices/lab_pin.sym} 1275 -1980 0 0 {name=p21 sig_type=std_logic lab=dvdd

}
C {sky130_fd_pr/nfet_01v8.sym} 1540 -2270 0 0 {name=M36
L=0.15
W=16
mult=8 nf=1
model=nfet_01v8
spiceprefix=X}
C {sky130_fd_pr/nfet_01v8.sym} 1440 -2270 0 1 {name=M37
L=0.15
W=16
mult=8 nf=1
model=nfet_01v8
spiceprefix=X}
C {devices/lab_pin.sym} 1420 -2200 0 0 {name=p58 sig_type=std_logic lab=dvss

}
C {devices/lab_pin.sym} 1560 -2270 0 1 {name=p60 sig_type=std_logic lab=dvss

}
C {devices/lab_pin.sym} 1420 -2270 0 0 {name=p61 sig_type=std_logic lab=dvss

}
C {devices/lab_pin.sym} 1480 -2330 0 1 {name=p62 sig_type=std_logic lab=hyst_bias1


}
C {devices/lab_pin.sym} 1280 -2440 0 0 {name=p24 sig_type=std_logic lab=dvdd

}
C {devices/lab_pin.sym} 1420 -2440 0 1 {name=p63 sig_type=std_logic lab=dvdd

}
C {devices/lab_pin.sym} 1370 -1685 0 0 {name=p28 sig_type=std_logic lab=hyst_bias0


}
C {devices/lab_pin.sym} 995 -480 0 1 {name=l33 lab=nbias_tail
}
C {sky130_fd_pr/nfet_01v8.sym} 1165 -1815 0 0 {name=M13
L=0.15
W=2
mult=2 nf=1
model=nfet_01v8
spiceprefix=X}
C {sky130_fd_pr/nfet_01v8.sym} 1165 -1685 0 0 {name=M18
L=0.15
W=2
mult=2 nf=1
model=nfet_01v8
spiceprefix=X}
C {devices/lab_pin.sym} 2485 -710 2 0 {name=l30 lab=SumOut
}
C {devices/vsource.sym} 3015 -1260 0 0 {name=V2 value=2.5 savecurrent=false}
C {devices/lab_pin.sym} 3015 -1290 0 0 {name=p15 sig_type=std_logic lab=Bias1


}
C {devices/lab_pin.sym} 3025 -1230 0 1 {name=p16 lab=avss
}
C {devices/lab_pin.sym} 2850 -670 2 1 {name=l9 lab=SumOut
}
C {devices/lab_pin.sym} 2345 -1450 0 1 {name=p45 lab=avss
}
C {devices/lab_pin.sym} 2970 -660 2 1 {name=l37 lab=SumOutBar
}
C {devices/lab_pin.sym} 2145 -1710 0 0 {name=p46 sig_type=std_logic lab=I_hyst

}
C {devices/lab_pin.sym} 2280 -1725 2 1 {name=l20 lab=SumOut
}
C {devices/lab_pin.sym} 2215 -730 2 0 {name=l36 lab=Sum
}
C {devices/lab_pin.sym} 2590 -1725 2 0 {name=l32 lab=SumOutBar
}
C {devices/vsource.sym} 2875 -1260 0 0 {name=V1 value=2.5 savecurrent=false}
C {devices/lab_pin.sym} 2875 -1290 0 0 {name=p14 sig_type=std_logic lab=Bias2


}
C {devices/lab_pin.sym} 2885 -1230 0 1 {name=p17 lab=avss
}
C {devices/lab_pin.sym} 2555 -640 0 1 {name=p22 sig_type=std_logic lab=Bias2


}
C {sky130_fd_pr/nfet_g5v0d10v5.sym} 2240 -2275 0 0 {name=M39
L=1
W=2
nf=1
mult=2
ad="'int((nf+1)/2) * W/nf * 0.29'" 
pd="'2*int((nf+1)/2) * (W/nf + 0.29)'"
as="'int((nf+2)/2) * W/nf * 0.29'" 
ps="'2*int((nf+2)/2) * (W/nf + 0.29)'"
nrd="'0.29 / W'" nrs="'0.29 / W'"
sa=0 sb=0 sd=0
model=nfet_g5v0d10v5
spiceprefix=X
}
C {sky130_fd_pr/nfet_g5v0d10v5.sym} 2080 -2275 0 1 {name=MHyst1
L=1
W=2
nf=1
mult=2
ad="'int((nf+1)/2) * W/nf * 0.29'" 
pd="'2*int((nf+1)/2) * (W/nf + 0.29)'"
as="'int((nf+2)/2) * W/nf * 0.29'" 
ps="'2*int((nf+2)/2) * (W/nf + 0.29)'"
nrd="'0.29 / W'" nrs="'0.29 / W'"
sa=0 sb=0 sd=0
model=nfet_g5v0d10v5
spiceprefix=X
}
C {devices/lab_pin.sym} 2260 -2275 0 1 {name=p29 lab=avss
}
C {devices/lab_pin.sym} 2060 -2275 0 0 {name=p51 lab=avss
}
C {devices/lab_pin.sym} 2260 -2195 0 1 {name=p65 lab=avss
}
C {devices/lab_pin.sym} 2060 -2455 0 0 {name=p66 sig_type=std_logic lab=I_hyst

}
C {devices/lab_pin.sym} 2620 -2070 2 0 {name=l6 lab=SumOut
}
C {devices/lab_pin.sym} 2310 -2070 2 1 {name=l47 lab=SumOutBar
}
C {sky130_fd_pr/pfet_g5v0d10v5.sym} 2535 -2070 0 1 {name=M41
L=1
W=2
nf=1
mult=2
ad="'int((nf+1)/2) * W/nf * 0.29'" 
pd="'2*int((nf+1)/2) * (W/nf + 0.29)'"
as="'int((nf+2)/2) * W/nf * 0.29'" 
ps="'2*int((nf+2)/2) * (W/nf + 0.29)'"
nrd="'0.29 / W'" nrs="'0.29 / W'"
sa=0 sb=0 sd=0
model=pfet_g5v0d10v5
spiceprefix=X
}
C {sky130_fd_pr/pfet_g5v0d10v5.sym} 2365 -2070 0 0 {name=M40
L=1
W=2
nf=1
mult=2
ad="'int((nf+1)/2) * W/nf * 0.29'" 
pd="'2*int((nf+1)/2) * (W/nf + 0.29)'"
as="'int((nf+2)/2) * W/nf * 0.29'" 
ps="'2*int((nf+2)/2) * (W/nf + 0.29)'"
nrd="'0.29 / W'" nrs="'0.29 / W'"
sa=0 sb=0 sd=0
model=pfet_g5v0d10v5
spiceprefix=X
}
C {devices/lab_pin.sym} 2515 -2070 0 0 {name=l48 lab=avdd
}
C {devices/lab_pin.sym} 2385 -2070 0 1 {name=l49 lab=avdd
}
C {sky130_fd_pr/pfet_g5v0d10v5.sym} 2280 -2450 0 1 {name=M42
L=1
W=2
nf=1
mult=2
ad="'int((nf+1)/2) * W/nf * 0.29'" 
pd="'2*int((nf+1)/2) * (W/nf + 0.29)'"
as="'int((nf+2)/2) * W/nf * 0.29'" 
ps="'2*int((nf+2)/2) * (W/nf + 0.29)'"
nrd="'0.29 / W'" nrs="'0.29 / W'"
sa=0 sb=0 sd=0
model=pfet_g5v0d10v5
spiceprefix=X
}
C {sky130_fd_pr/pfet_01v8.sym} 2430 -2450 0 0 {name=M43
L=0.15
W=2
nf=1
mult=2
ad="'int((nf+1)/2) * W/nf * 0.29'" 
pd="'2*int((nf+1)/2) * (W/nf + 0.29)'"
as="'int((nf+2)/2) * W/nf * 0.29'" 
ps="'2*int((nf+2)/2) * (W/nf + 0.29)'"
nrd="'0.29 / W'" nrs="'0.29 / W'"
sa=0 sb=0 sd=0
model=pfet_01v8
spiceprefix=X
}
C {devices/lab_pin.sym} 2450 -2450 0 1 {name=l50 lab=avdd
}
C {devices/lab_pin.sym} 2260 -2450 0 0 {name=l51 lab=avdd
}
C {devices/lab_pin.sym} 2260 -2545 0 0 {name=l52 lab=avdd
}
C {devices/lab_pin.sym} 2390 -2010 0 1 {name=l38 lab=avdd
}
C {devices/lab_pin.sym} 2515 -2015 0 1 {name=l46 lab=avdd
}
C {devices/lab_pin.sym} 2485 -1870 0 1 {name=p52 lab=avss
}
C {devices/lab_pin.sym} 2360 -1870 0 1 {name=p64 lab=avss
}
C {devices/isource.sym} 1315 -1105 0 0 {name=I2 value=1u}
C {devices/isource.sym} 1355 -355 0 0 {name=I3 value=1u}
C {devices/lab_pin.sym} 1355 -325 0 1 {name=p13 sig_type=std_logic lab=avss


}
